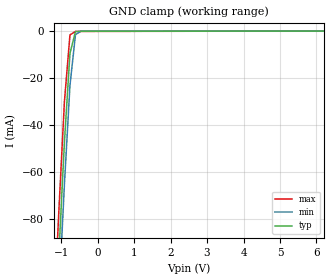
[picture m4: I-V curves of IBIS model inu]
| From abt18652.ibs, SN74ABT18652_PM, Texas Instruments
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[Model]   inu
| input buffer with pullup resistor
| inu18502.abt (95265 SRIJ)
| pad18502.abt (95265 SRIJ)
Model_type   Input
Polarity   Non-Inverting
| Signals   TDI, TMS
Vinl = 0.8V
Vinh = 2.0V
| variable   typ   min   max
C_comp   5pF   NA   NA
| variable   typ   min   max
[Voltage range]   5.0V   4.5V   5.5V
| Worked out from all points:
|   GND clamp passes 1 mA (typ) near -0.62 V on its own axis
[gnd_clamp]
|   50C:5V:   100C:4.5V:weak   0C:5.5V:strong
|   Voltage   I(typ)   I(min)   I(max)
-5V       -1.478A    -1.494A    -1.463A
-1.212V   -144.3mA   -162.9mA   -126.1mA
-1.061V   -94.4mA    -112.9mA   -76.15mA
-909.1mV  -47.2mA    -65.12mA   -29.94mA
-757.6mV  -9.439mA   -23.08mA   -1.622mA
-606.1mV  -197.6uA   -1.505mA   -143.6uA
-454.5mV  -80.26uA   -66.02uA   -136.8uA
10V       45.03nA    1.369uA    2.843nA
